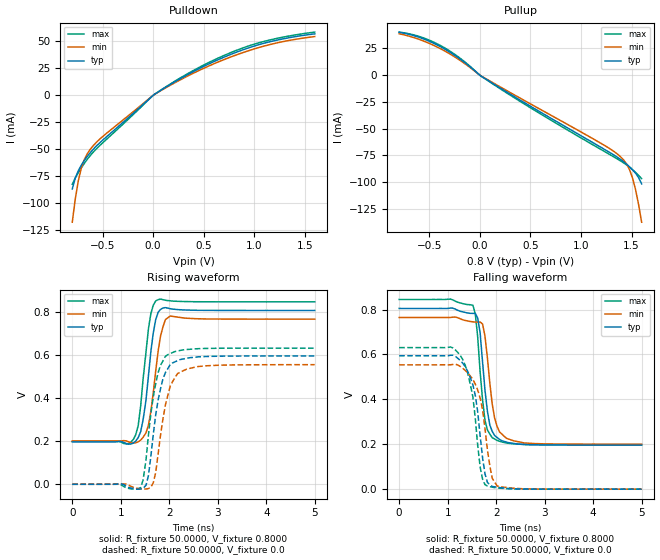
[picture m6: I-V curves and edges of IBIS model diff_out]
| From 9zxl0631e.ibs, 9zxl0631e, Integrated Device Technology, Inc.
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|   Model diff_out (lphcsl_0v8_fast)
[Model] diff_out
Model_type Output
Polarity   Non-Inverting
Vmeas =  0.4000V
Cref =   2.0000pF
Rref =   0.0
Vref =   0.4000V
C_comp   1.1000pF   1.0000pF   1.2000pF
[Temperature Range]   27.0000   70.0000   0.0
[Voltage Range]   0.8000V   0.7600V   0.8400V
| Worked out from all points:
|   slope of the pulldown table from 0 to 0.12 V, typ, clamps not added: 16.5 ohm
|   slope of the pullup table from 0 to 0.12 V, typ, clamps not added: 16.7 ohm
|   rising waveform, R_fixture 50.0000, V_fixture 0.8000: 20-80 % time 187ps typ, 194ps min, 178ps max; typ from 0.196 V to 0.805 V
|   rising waveform, R_fixture 50.0000, V_fixture 0.0: 20-80 % time 241ps typ, 254ps min, 232ps max; typ from 0 V to 0.594 V
|   falling waveform, R_fixture 50.0000, V_fixture 0.8000: 20-80 % time 169ps typ, 188ps min, 157ps max; typ from 0.805 V to 0.196 V
|   falling waveform, R_fixture 50.0000, V_fixture 0.0: 20-80 % time 233ps typ, 248ps min, 230ps max; typ from 0.594 V to 0 V
[Pulldown]
|Voltage   I(typ)   I(min)   I(max)
-800mV    -86.9mA    -117.8mA   -82.54mA
-770mV    -76.78mA   -96.06mA   -76.76mA
-740mV    -69.97mA   -79.24mA   -71.83mA
-710mV    -64.83mA   -67.4mA    -67.32mA
-680mV    -60.48mA   -59.5mA    -63.13mA
-650mV    -56.6mA    -54.04mA   -59.26mA
-530mV    -44.34mA   -40.87mA   -46.9mA
-20mV     -1.744mA   -1.577mA   -1.865mA
370mV     20.51mA    19.13mA    21.48mA
790mV     38.68mA    36.26mA    40.35mA
1.15V     49.5mA     46.87mA    51.16mA
1.6V      56.96mA    54.45mA    58.6mA
[Pullup]
|Voltage  I(typ)   I(min)   I(max)
-800mV    39.81mA    38.43mA    39.97mA
-560mV    33.66mA    31.69mA    34.58mA
-350mV    24.19mA    22.41mA    25.24mA
-170mV    12.93mA    11.84mA    13.64mA
10mV      -1.08mA    -973uA     -1.145mA
250mV     -15.1mA    -13.83mA   -15.92mA
1.36V     -76.81mA   -73.82mA   -78.4mA
1.45V     -83.13mA   -82.99mA   -83.89mA
1.51V     -88.47mA   -96.18mA   -88.4mA
1.54V     -91.67mA   -107mA     -90.97mA
1.57V     -95.76mA   -120.9mA   -93.75mA
1.6V      -101.7mA   -137.4mA   -96.74mA
[Ramp]
| variable   typ   min   max
dV/dt_r  0.3566/0.2414n   0.3323/0.2535n   0.3784/0.2317n
dV/dt_f  0.3620/0.1686n   0.3358/0.1883n   0.3847/0.1572n
R_load = 50.0000
[Rising Waveform]
R_fixture= 50.0000
V_fixture= 0.8000
V_fixture_min= 0.7600
V_fixture_max= 0.8400
|time   V(typ)   V(min)   V(max)
0s        196.4mV    200.5mV    198.1mV
1.26ns    191.2mV    190.4mV    207.9mV
1.36ns    216.3mV    196.7mV    272.6mV
1.46ns    298.3mV    217.6mV    486.6mV
1.57ns    501.5mV    273.4mV    719mV
1.72ns    762.7mV    523.6mV    849mV
1.82ns    809.9mV    686.6mV    857.8mV
1.92ns    818.2mV    762.6mV    852.2mV
2.02ns    813.2mV    779.2mV    849.6mV
5ns       805mV      764.8mV    845mV
[Rising Waveform]
R_fixture= 50.0000
V_fixture= 0.0
V_fixture_min= 0.0
V_fixture_max= 0.0
|time   V(typ)   V(min)   V(max)
0s        572.4nV    0V         681.4nV
1.41ns    -21.84mV   -21.24mV   -15.64mV
1.46ns    -18.98mV   -22.2mV    19.49mV
1.57ns    39.87mV    -20.03mV   227.1mV
1.67ns    229.9mV    6.387mV    404.7mV
1.82ns    442.4mV    228.5mV    551.1mV
1.97ns    535.6mV    411.1mV    600.1mV
2.17ns    572.4mV    512.5mV    617.2mV
2.58ns    589.8mV    545mV      627.8mV
5ns       594.4mV    553.9mV    630.6mV
[Falling Waveform]
R_fixture= 50.0000
V_fixture= 0.8000
V_fixture_min= 0.7600
V_fixture_max= 0.8400
|time   V(typ)   V(min)   V(max)
0s        805mV      764.8mV    845mV
1.52ns    783.2mV    745.5mV    819.5mV
1.57ns    782.7mV    744.4mV    781.3mV
1.62ns    762.2mV    744.6mV    676.9mV
1.72ns    566.3mV    735.8mV    397.7mV
1.82ns    347.4mV    584.8mV    264mV
1.92ns    257mV      377.7mV    229.2mV
2.07ns    221.6mV    255.1mV    213.1mV
2.37ns    203.4mV    214.9mV    201.8mV
5ns       196.4mV    200.5mV    198.1mV
[Falling Waveform]
R_fixture= 50.0000
V_fixture= 0.0
V_fixture_min= 0.0
V_fixture_max= 0.0
|time   V(typ)   V(min)   V(max)
0s        594.4mV    553.9mV    630.6mV
1.26ns    573mV      546.8mV    596.2mV
1.41ns    526.5mV    519.2mV    519.6mV
1.52ns    464.9mV    489.1mV    411.6mV
1.57ns    418mV      468.3mV    315.8mV
1.67ns    238.5mV    405.9mV    99.52mV
1.77ns    68.2mV     270.2mV    19.82mV
1.92ns    11.95mV    48.11mV    8.729mV
2.02ns    8.538mV    14.34mV    5.537mV
5ns       795.4nV    918nV      864.5nV
